VERSION 5.7 ;
  NOWIREEXTENSIONATPIN ON ;
  DIVIDERCHAR "/" ;
  BUSBITCHARS "[]" ;
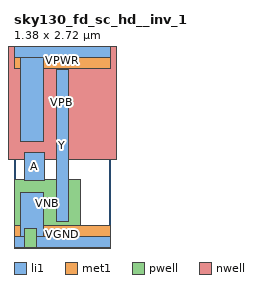
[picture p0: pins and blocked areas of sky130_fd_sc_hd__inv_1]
MACRO sky130_fd_sc_hd__inv_1
  CLASS CORE ;
  FOREIGN sky130_fd_sc_hd__inv_1 ;
  ORIGIN 0.000 0.000 ;
  SIZE 1.380 BY 2.720 ;
  SITE unithd ;
  PIN A
    DIRECTION INPUT ;
    USE SIGNAL ;
    ANTENNAGATEAREA 0.232500 ;
    PORT
      LAYER li1 ;
        RECT 0.145 0.880 0.435 1.275 ;
    END
  END A
  PIN VGND
    DIRECTION INOUT ;
    USE GROUND ;
    PORT
      LAYER li1 ;
        RECT 0.095 0.085 0.425 0.710 ;
        RECT 0.000 -0.085 1.380 0.085 ;
      LAYER met1 ;
        RECT 0.000 -0.240 1.380 0.240 ;
    END
  END VGND
  PIN VNB
    DIRECTION INOUT ;
    USE GROUND ;
    PORT
      LAYER pwell ;
        RECT 0.005 0.190 0.945 0.900 ;
        RECT 0.150 -0.085 0.325 0.190 ;
    END
  END VNB
  PIN VPB
    DIRECTION INOUT ;
    USE POWER ;
    PORT
      LAYER nwell ;
        RECT -0.190 1.185 1.570 2.910 ;
    END
  END VPB
  PIN VPWR
    DIRECTION INOUT ;
    USE POWER ;
    PORT
      LAYER li1 ;
        RECT 0.000 2.635 1.380 2.805 ;
        RECT 0.095 1.445 0.425 2.635 ;
      LAYER met1 ;
        RECT 0.000 2.480 1.380 2.960 ;
    END
  END VPWR
  PIN Y
    DIRECTION OUTPUT ;
    USE SIGNAL ;
    ANTENNADIFFAREA 0.410750 ;
    PORT
      LAYER li1 ;
        RECT 0.605 0.300 0.775 2.465 ;
    END
  END Y
  OBS
      LAYER pwell ;
        RECT 0.605 0.960 0.775 1.135 ;
  END
END sky130_fd_sc_hd__inv_1
END LIBRARY

